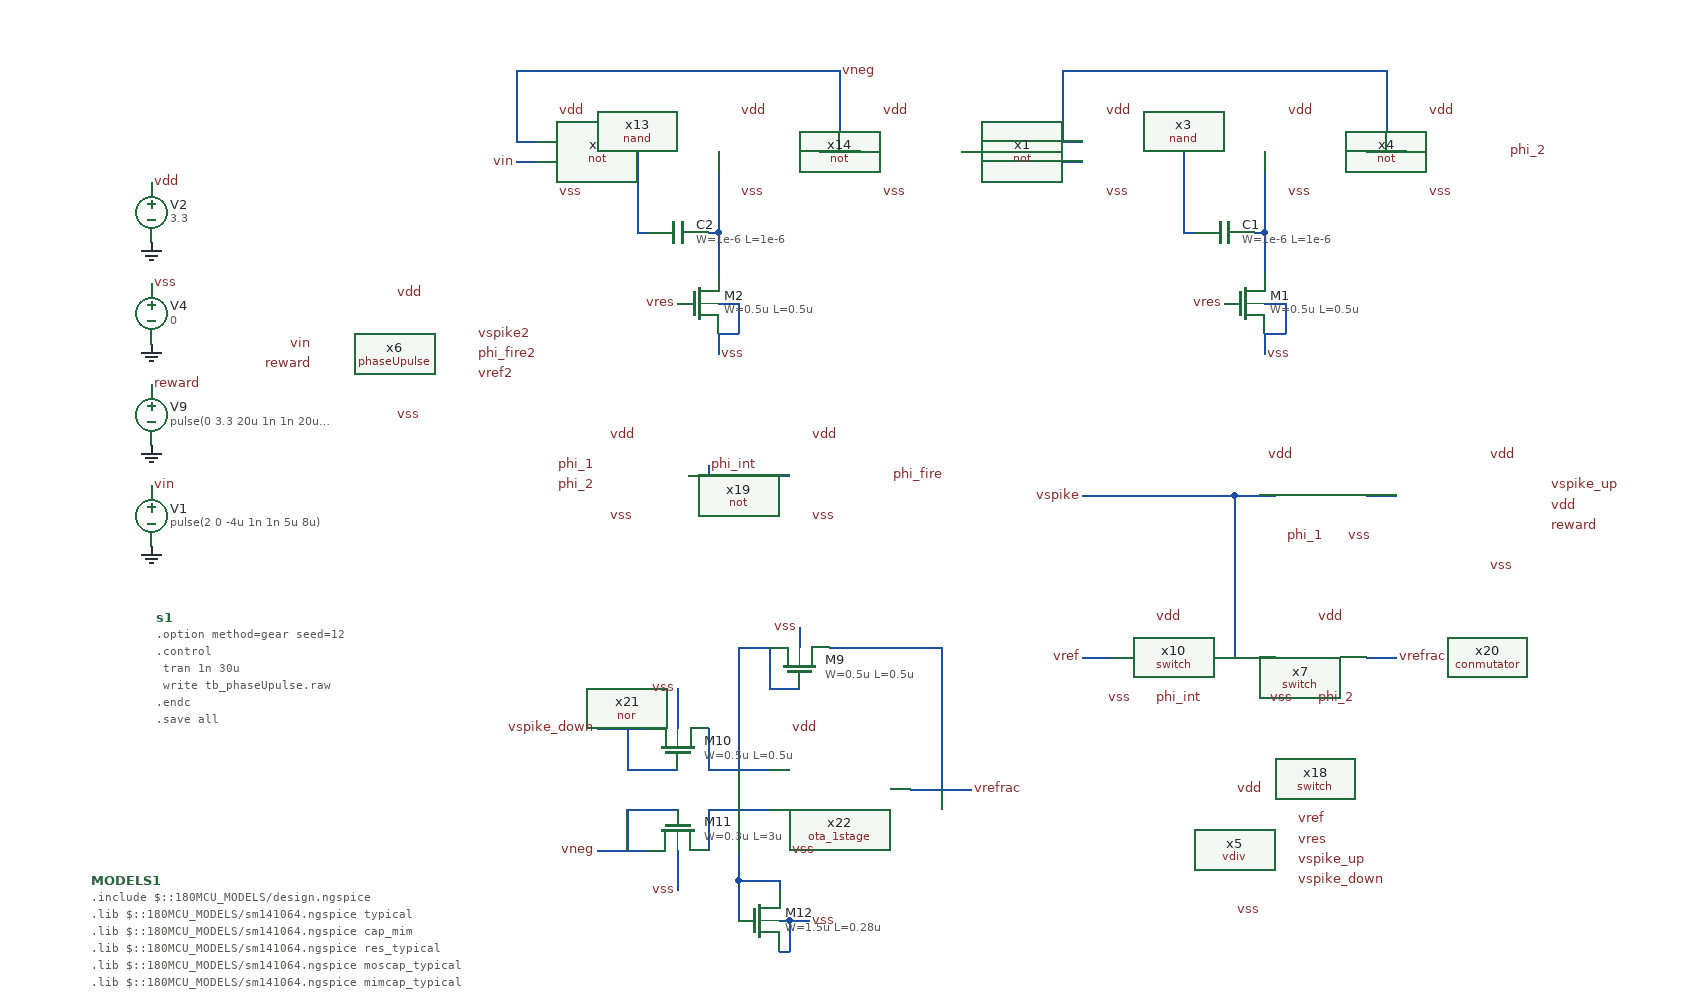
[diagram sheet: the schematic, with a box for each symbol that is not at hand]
v {xschem version=3.4.7 file_version=1.2}
G {}
K {}
V {}
S {}
E {}
B 2 1640 -1400 2440 -1200 {flags=graph
y1=-0.0017
y2=3.4
ypos1=0
ypos2=2
divy=5
subdivy=1
unity=1
x1=0
x2=3e-05
divx=5
subdivx=1
xlabmag=1.0
ylabmag=1.0
node="vin
phi_1
reward"
color="4 8 6"
dataset=-1
unitx=1
logx=0
logy=0
legend=1}
B 2 1640 -1200 2440 -1000 {flags=graph
y1=-0.0017
y2=3.4
ypos1=0
ypos2=2
divy=5
subdivy=1
unity=1
x1=0
x2=3e-05
divx=5
subdivx=1
xlabmag=1.0
ylabmag=1.0
node="phi_1
phi_2
phi_2b"
color="8 6 12"
dataset=-1
unitx=1
logx=0
logy=0
legend=1}
B 2 1640 -1000 2440 -800 {flags=graph
y1=-0.0017
y2=3.4
ypos1=0
ypos2=2
divy=5
subdivy=1
unity=1
x1=0
x2=3e-05
divx=5
subdivx=1
xlabmag=1.0
ylabmag=1.0
node="phi_int
phi_fire"
color="4 7"
dataset=-1
unitx=1
logx=0
logy=0
legend=1}
B 2 1640 -810 2440 -410 {flags=graph
y1=0.049
y2=3.4
ypos1=0
ypos2=2
divy=5
subdivy=1
unity=1
x1=0
x2=3e-05
divx=5
subdivx=1
xlabmag=1.0
ylabmag=1.0
node=vspike
color=10
dataset=-1
unitx=1
logx=0
logy=0
}
B 2 1640 -410 2440 -10 {flags=graph
y1=0.049
y2=3.4
ypos1=0
ypos2=2
divy=5
subdivy=1
unity=1
x1=0
x2=3e-05
divx=5
subdivx=1
xlabmag=1.0
ylabmag=1.0
node=vspike2
color=4
dataset=-1
unitx=1
logx=0
logy=0
}
N 420 -910 440 -910 {lab=vin}
N 620 -770 640 -770 {lab=vss}
N 640 -770 640 -740 {lab=vss}
N 620 -740 640 -740 {lab=vss}
N 620 -740 620 -720 {lab=vss}
N 720 -920 760 -920 {lab=vneg}
N 420 -930 440 -930 {lab=vneg}
N 420 -1000 420 -930 {lab=vneg}
N 420 -1000 740 -1000 {lab=vneg}
N 740 -1000 740 -920 {lab=vneg}
N 540 -920 540 -840 {lab=#net1}
N 540 -840 550 -840 {lab=#net1}
N 610 -840 620 -840 {lab=#net2}
N 620 -920 620 -840 {lab=#net2}
N 620 -840 620 -800 {lab=#net2}
N 960 -910 980 -910 {lab=phi_1}
N 1160 -770 1180 -770 {lab=vss}
N 1180 -770 1180 -740 {lab=vss}
N 1160 -740 1180 -740 {lab=vss}
N 1160 -740 1160 -720 {lab=vss}
N 1260 -920 1300 -920 {lab=#net3}
N 960 -930 980 -930 {lab=#net3}
N 960 -1000 960 -930 {lab=#net3}
N 960 -1000 1280 -1000 {lab=#net3}
N 1280 -1000 1280 -920 {lab=#net3}
N 1080 -920 1080 -840 {lab=#net4}
N 1080 -840 1090 -840 {lab=#net4}
N 1150 -840 1160 -840 {lab=#net5}
N 1160 -920 1160 -840 {lab=#net5}
N 1160 -840 1160 -800 {lab=#net5}
N 860 -920 880 -920 {lab=phi_1}
N 880 -920 880 -910 {lab=phi_1}
N 880 -910 960 -910 {lab=phi_1}
N 590 -600 690 -600 {lab=phi_int}
N 610 -610 610 -600 {lab=phi_int}
N 610 -310 670 -310 {lab=#net6}
N 810 -290 870 -290 {lab=vrefrac}
N 700 -450 700 -430 {lab=vss}
N 670 -430 670 -390 {lab=#net6}
N 670 -390 700 -390 {lab=#net6}
N 640 -430 640 -310 {lab=#net6}
N 640 -430 670 -430 {lab=#net6}
N 730 -430 840 -430 {lab=vrefrac}
N 840 -430 840 -290 {lab=vrefrac}
N 540 -350 550 -350 {lab=vspike_down}
N 500 -350 540 -350 {lab=vspike_down}
N 530 -310 580 -310 {lab=vspike_down}
N 530 -350 530 -310 {lab=vspike_down}
N 610 -350 610 -310 {lab=#net6}
N 500 -230 550 -230 {lab=vneg}
N 530 -270 580 -270 {lab=vneg}
N 530 -270 530 -230 {lab=vneg}
N 610 -270 610 -230 {lab=#net7}
N 610 -270 670 -270 {lab=#net7}
N 580 -390 580 -350 {lab=vss}
N 580 -230 580 -190 {lab=vss}
N 640 -270 640 -200 {lab=#net7}
N 640 -200 680 -200 {lab=#net7}
N 680 -200 680 -190 {lab=#net7}
N 640 -200 640 -160 {lab=#net7}
N 680 -160 690 -160 {lab=vss}
N 690 -160 690 -130 {lab=vss}
N 680 -130 690 -130 {lab=vss}
N 690 -160 710 -160 {lab=vss}
N 980 -420 1010 -420 {lab=vref}
N 1260 -420 1290 -420 {lab=vrefrac}
N 1100 -420 1170 -420 {lab=vspike}
N 1130 -560 1130 -420 {lab=vspike}
N 980 -580 1130 -580 {lab=vspike}
N 1130 -580 1130 -560 {lab=vspike}
N 1130 -580 1170 -580 {lab=vspike}
N 1260 -580 1290 -580 {lab=#net8}
C {title.sym} 160 0 0 0 {name=l1 author="Oscar Islas"}
C {vsource.sym} 60 -560 0 1 {name=V1 value="pulse(2 0 -4u 1n 1n 5u 8u)" savecurrent=false}
C {gnd.sym} 60 -530 0 0 {name=l5 lab=GND}
C {lab_pin.sym} 60 -590 0 1 {name=p86 sig_type=std_logic lab=vin}
C {vsource.sym} 60 -860 0 1 {name=V2 value=3.3 savecurrent=false}
C {gnd.sym} 60 -830 0 0 {name=l6 lab=GND}
C {lab_pin.sym} 60 -890 0 1 {name=p87 sig_type=std_logic lab=vdd}
C {launcher.sym} 1420 -300 0 0 {name=h5
descr="load waves" 
tclcommand="xschem raw_read $netlist_dir/tb_phaseUpulse.raw tran"
}
C {devices/code_shown.sym} 65 -460 0 0 {name=s1 only_toplevel=false value="
.option method=gear seed=12
.control
    tran 1n 30u
    write tb_phaseUpulse.raw
.endc
.save all
"
spice_ignore=False}
C {devices/code_shown.sym} 0 -200 0 0 {name=MODELS1 only_toplevel=true
format="tcleval( @value )"
value="
.include $::180MCU_MODELS/design.ngspice
.lib $::180MCU_MODELS/sm141064.ngspice typical
.lib $::180MCU_MODELS/sm141064.ngspice cap_mim
.lib $::180MCU_MODELS/sm141064.ngspice res_typical
.lib $::180MCU_MODELS/sm141064.ngspice moscap_typical
.lib $::180MCU_MODELS/sm141064.ngspice mimcap_typical
"}
C {gnd.sym} 60 -730 0 0 {name=l3 lab=GND}
C {lab_pin.sym} 60 -790 0 1 {name=p1 sig_type=std_logic lab=vss}
C {vsource.sym} 60 -760 0 1 {name=V4 value=0 savecurrent=false}
C {vsource.sym} 60 -660 0 1 {name=V9 value="pulse(0 3.3 20u 1n 1n 20u 40u)" savecurrent=false}
C {gnd.sym} 60 -630 0 0 {name=l10 lab=GND}
C {lab_pin.sym} 60 -690 0 1 {name=p57 sig_type=std_logic lab=reward}
C {designs/libs/core_LIF_comp/core_not/not.sym} 460 -930 0 0 {name=x2}
C {lab_pin.sym} 420 -910 0 0 {name=p10 sig_type=std_logic lab=vin}
C {lab_pin.sym} 460 -960 2 0 {name=p13 sig_type=std_logic lab=vdd}
C {symbols/nfet_03v3.sym} 600 -770 0 0 {name=M2
L=0.5u
W=0.5u
nf=1
m=1
ad="'int((nf+1)/2) * W/nf * 0.18u'"
pd="'2*int((nf+1)/2) * (W/nf + 0.18u)'"
as="'int((nf+2)/2) * W/nf * 0.18u'"
ps="'2*int((nf+2)/2) * (W/nf + 0.18u)'"
nrd="'0.18u / W'" nrs="'0.18u / W'"
sa=0 sb=0 sd=0
model=nfet_03v3
spiceprefix=X
}
C {designs/libs/core_LIF_comp/core_nand/nand.sym} 480 -920 0 0 {name=x13}
C {designs/libs/core_LIF_comp/core_not/not.sym} 600 -930 0 0 {name=x14}
C {lab_pin.sym} 640 -960 2 0 {name=p84 sig_type=std_logic lab=vdd}
C {lab_pin.sym} 780 -960 2 0 {name=p85 sig_type=std_logic lab=vdd}
C {symbols/cap_mim_2f0fF.sym} 580 -840 3 0 {name=C2
W=1e-6
L=1e-6
model=cap_mim_2f0fF
spiceprefix=X
m=2}
C {lab_pin.sym} 460 -880 2 0 {name=p11 sig_type=std_logic lab=vss}
C {lab_pin.sym} 640 -880 2 0 {name=p12 sig_type=std_logic lab=vss}
C {lab_pin.sym} 780 -880 2 0 {name=p14 sig_type=std_logic lab=vss}
C {lab_pin.sym} 620 -720 2 0 {name=p15 sig_type=std_logic lab=vss}
C {lab_pin.sym} 580 -770 2 1 {name=p16 sig_type=std_logic lab=vres}
C {lab_pin.sym} 880 -920 2 0 {name=p53 sig_type=std_logic lab=phi_1}
C {designs/libs/core_LIF_comp/core_not/not.sym} 1000 -930 0 0 {name=x1}
C {lab_pin.sym} 1000 -960 2 0 {name=p9 sig_type=std_logic lab=vdd}
C {symbols/nfet_03v3.sym} 1140 -770 0 0 {name=M1
L=0.5u
W=0.5u
nf=1
m=1
ad="'int((nf+1)/2) * W/nf * 0.18u'"
pd="'2*int((nf+1)/2) * (W/nf + 0.18u)'"
as="'int((nf+2)/2) * W/nf * 0.18u'"
ps="'2*int((nf+2)/2) * (W/nf + 0.18u)'"
nrd="'0.18u / W'" nrs="'0.18u / W'"
sa=0 sb=0 sd=0
model=nfet_03v3
spiceprefix=X
}
C {designs/libs/core_LIF_comp/core_nand/nand.sym} 1020 -920 0 0 {name=x3}
C {designs/libs/core_LIF_comp/core_not/not.sym} 1140 -930 0 0 {name=x4}
C {lab_pin.sym} 1180 -960 2 0 {name=p2 sig_type=std_logic lab=vdd}
C {lab_pin.sym} 1320 -960 2 0 {name=p18 sig_type=std_logic lab=vdd}
C {symbols/cap_mim_2f0fF.sym} 1120 -840 3 0 {name=C1
W=1e-6
L=1e-6
model=cap_mim_2f0fF
spiceprefix=X
m=2}
C {lab_pin.sym} 1000 -880 2 0 {name=p19 sig_type=std_logic lab=vss}
C {lab_pin.sym} 1180 -880 2 0 {name=p20 sig_type=std_logic lab=vss}
C {lab_pin.sym} 1320 -880 2 0 {name=p21 sig_type=std_logic lab=vss}
C {lab_pin.sym} 1160 -720 2 0 {name=p22 sig_type=std_logic lab=vss}
C {lab_pin.sym} 1120 -770 2 1 {name=p23 sig_type=std_logic lab=vres}
C {lab_pin.sym} 1400 -920 2 0 {name=p24 sig_type=std_logic lab=phi_2}
C {designs/libs/core_LIF_comp/core_not/not.sym} 530 -610 0 0 {name=x19}
C {designs/libs/core_LIF_comp/core_nor/nor.sym} 540 -520 0 0 {name=x21}
C {lab_pin.sym} 510 -640 2 0 {name=p89 sig_type=std_logic lab=vdd}
C {lab_pin.sym} 710 -640 2 0 {name=p99 sig_type=std_logic lab=vdd}
C {lab_pin.sym} 610 -610 2 0 {name=p100 sig_type=std_logic lab=phi_int}
C {lab_pin.sym} 510 -560 2 0 {name=p101 sig_type=std_logic lab=vss}
C {lab_pin.sym} 710 -560 2 0 {name=p107 sig_type=std_logic lab=vss}
C {lab_pin.sym} 500 -610 2 1 {name=p108 sig_type=std_logic lab=phi_1}
C {lab_pin.sym} 500 -590 2 1 {name=p109 sig_type=std_logic lab=phi_2}
C {lab_pin.sym} 790 -600 2 0 {name=p110 sig_type=std_logic lab=phi_fire}
C {lab_pin.sym} 740 -1000 2 0 {name=p25 sig_type=std_logic lab=vneg}
C {designs/libs/core_LIF_comp/core_ota_1stage/ota_1stage.sym} 710 -290 0 0 {name=x22}
C {lab_pin.sym} 870 -290 2 0 {name=p111 sig_type=std_logic lab=vrefrac}
C {lab_pin.sym} 500 -350 0 0 {name=p113 sig_type=std_logic lab=vspike_down}
C {lab_pin.sym} 690 -350 2 0 {name=p116 sig_type=std_logic lab=vdd}
C {lab_pin.sym} 690 -230 2 0 {name=p117 sig_type=std_logic lab=vss}
C {symbols/nfet_03v3.sym} 700 -410 3 0 {name=M9
L=0.5u
W=0.5u
nf=1
m=1
ad="'int((nf+1)/2) * W/nf * 0.18u'"
pd="'2*int((nf+1)/2) * (W/nf + 0.18u)'"
as="'int((nf+2)/2) * W/nf * 0.18u'"
ps="'2*int((nf+2)/2) * (W/nf + 0.18u)'"
nrd="'0.18u / W'" nrs="'0.18u / W'"
sa=0 sb=0 sd=0
model=nfet_03v3
spiceprefix=X
}
C {lab_pin.sym} 700 -450 1 0 {name=p123 sig_type=std_logic lab=vss}
C {symbols/nfet_03v3.sym} 580 -330 3 0 {name=M10
L=0.5u
W=0.5u
nf=1
m=1
ad="'int((nf+1)/2) * W/nf * 0.18u'"
pd="'2*int((nf+1)/2) * (W/nf + 0.18u)'"
as="'int((nf+2)/2) * W/nf * 0.18u'"
ps="'2*int((nf+2)/2) * (W/nf + 0.18u)'"
nrd="'0.18u / W'" nrs="'0.18u / W'"
sa=0 sb=0 sd=0
model=nfet_03v3
spiceprefix=X
}
C {symbols/nfet_03v3.sym} 580 -250 3 1 {name=M11
L=3u
W=0.3u
nf=1
m=1
ad="'int((nf+1)/2) * W/nf * 0.18u'"
pd="'2*int((nf+1)/2) * (W/nf + 0.18u)'"
as="'int((nf+2)/2) * W/nf * 0.18u'"
ps="'2*int((nf+2)/2) * (W/nf + 0.18u)'"
nrd="'0.18u / W'" nrs="'0.18u / W'"
sa=0 sb=0 sd=0
model=nfet_03v3
spiceprefix=X
}
C {symbols/nfet_03v3.sym} 660 -160 0 0 {name=M12
L=0.28u
W=1.5u
nf=1
m=1
ad="'int((nf+1)/2) * W/nf * 0.18u'"
pd="'2*int((nf+1)/2) * (W/nf + 0.18u)'"
as="'int((nf+2)/2) * W/nf * 0.18u'"
ps="'2*int((nf+2)/2) * (W/nf + 0.18u)'"
nrd="'0.18u / W'" nrs="'0.18u / W'"
sa=0 sb=0 sd=0
model=nfet_03v3
spiceprefix=X
}
C {lab_pin.sym} 710 -160 2 0 {name=p124 sig_type=std_logic lab=vss}
C {lab_pin.sym} 580 -190 1 1 {name=p125 sig_type=std_logic lab=vss}
C {lab_pin.sym} 500 -230 2 1 {name=p122 sig_type=std_logic lab=vneg}
C {lab_pin.sym} 580 -390 3 1 {name=p26 sig_type=std_logic lab=vss}
C {designs/libs/core_LIF_comp/core_switch/switch.sym} 1220 -460 0 0 {name=x7}
C {lab_pin.sym} 1190 -620 1 0 {name=p82 sig_type=std_logic lab=vdd}
C {lab_pin.sym} 1240 -540 2 0 {name=p83 sig_type=std_logic lab=vss}
C {lab_pin.sym} 1220 -540 0 0 {name=p88 sig_type=std_logic lab=phi_1}
C {lab_pin.sym} 980 -420 2 1 {name=p90 sig_type=std_logic lab=vref}
C {lab_pin.sym} 980 -580 0 0 {name=p91 sig_type=std_logic lab=vspike}
C {designs/libs/core_LIF_comp/core_switch/switch.sym} 1050 -300 0 1 {name=x10}
C {lab_pin.sym} 1080 -460 3 1 {name=p92 sig_type=std_logic lab=vdd}
C {lab_pin.sym} 1030 -380 2 1 {name=p93 sig_type=std_logic lab=vss}
C {lab_pin.sym} 1050 -380 0 1 {name=p94 sig_type=std_logic lab=phi_int}
C {designs/libs/core_LIF_comp/core_switch/switch.sym} 1210 -300 0 1 {name=x18}
C {lab_pin.sym} 1240 -460 3 1 {name=p95 sig_type=std_logic lab=vdd}
C {lab_pin.sym} 1190 -380 2 1 {name=p96 sig_type=std_logic lab=vss}
C {lab_pin.sym} 1210 -380 0 1 {name=p97 sig_type=std_logic lab=phi_2}
C {lab_pin.sym} 1290 -420 2 0 {name=p98 sig_type=std_logic lab=vrefrac}
C {designs/libs/core_LIF_comp/core_conmutator/conmutator.sym} 1380 -420 0 1 {name=x20}
C {lab_pin.sym} 1380 -620 2 0 {name=p102 sig_type=std_logic lab=vdd}
C {lab_pin.sym} 1380 -510 2 0 {name=p103 sig_type=std_logic lab=vss}
C {lab_pin.sym} 1440 -590 2 0 {name=p105 sig_type=std_logic lab=vspike_up}
C {lab_pin.sym} 1440 -550 2 0 {name=p106 sig_type=std_logic lab=reward}
C {designs/libs/core_LIF_comp/core_vdiv/vdiv.sym} 1130 -230 0 0 {name=x5}
C {lab_pin.sym} 1130 -290 2 0 {name=p27 sig_type=std_logic lab=vdd}
C {lab_pin.sym} 1130 -170 2 0 {name=p28 sig_type=std_logic lab=vss}
C {lab_pin.sym} 1190 -260 2 0 {name=p29 sig_type=std_logic lab=vref}
C {lab_pin.sym} 1190 -240 2 0 {name=p30 sig_type=std_logic lab=vres}
C {lab_pin.sym} 1190 -220 2 0 {name=p31 sig_type=std_logic lab=vspike_up}
C {lab_pin.sym} 1190 -200 2 0 {name=p32 sig_type=std_logic lab=vspike_down}
C {lab_pin.sym} 1440 -570 2 0 {name=p33 sig_type=std_logic lab=vdd}
C {designs/libs/core_LIF_comp/core_phaseUpulse/phaseUpulse.sym} 300 -720 0 0 {name=x6}
C {lab_pin.sym} 220 -730 0 0 {name=p3 sig_type=std_logic lab=vin}
C {lab_pin.sym} 300 -780 2 0 {name=p4 sig_type=std_logic lab=vdd}
C {lab_pin.sym} 300 -660 2 0 {name=p5 sig_type=std_logic lab=vss}
C {lab_pin.sym} 380 -740 2 0 {name=p6 sig_type=std_logic lab=vspike2}
C {lab_pin.sym} 380 -720 2 0 {name=p7 sig_type=std_logic lab=phi_fire2}
C {lab_pin.sym} 380 -700 2 0 {name=p8 sig_type=std_logic lab=vref2}
C {lab_pin.sym} 220 -710 0 0 {name=p17 sig_type=std_logic lab=reward}
